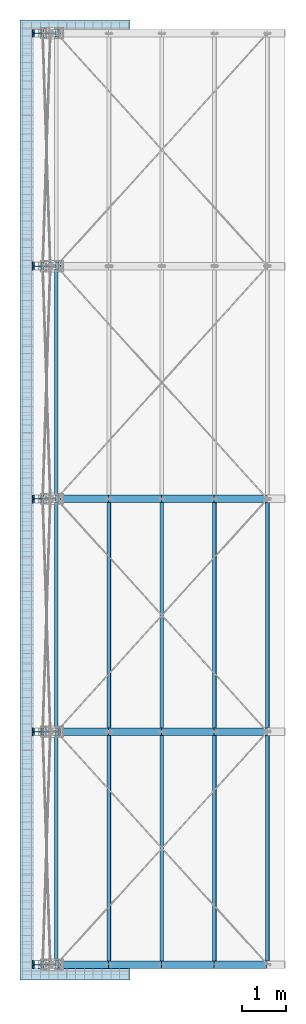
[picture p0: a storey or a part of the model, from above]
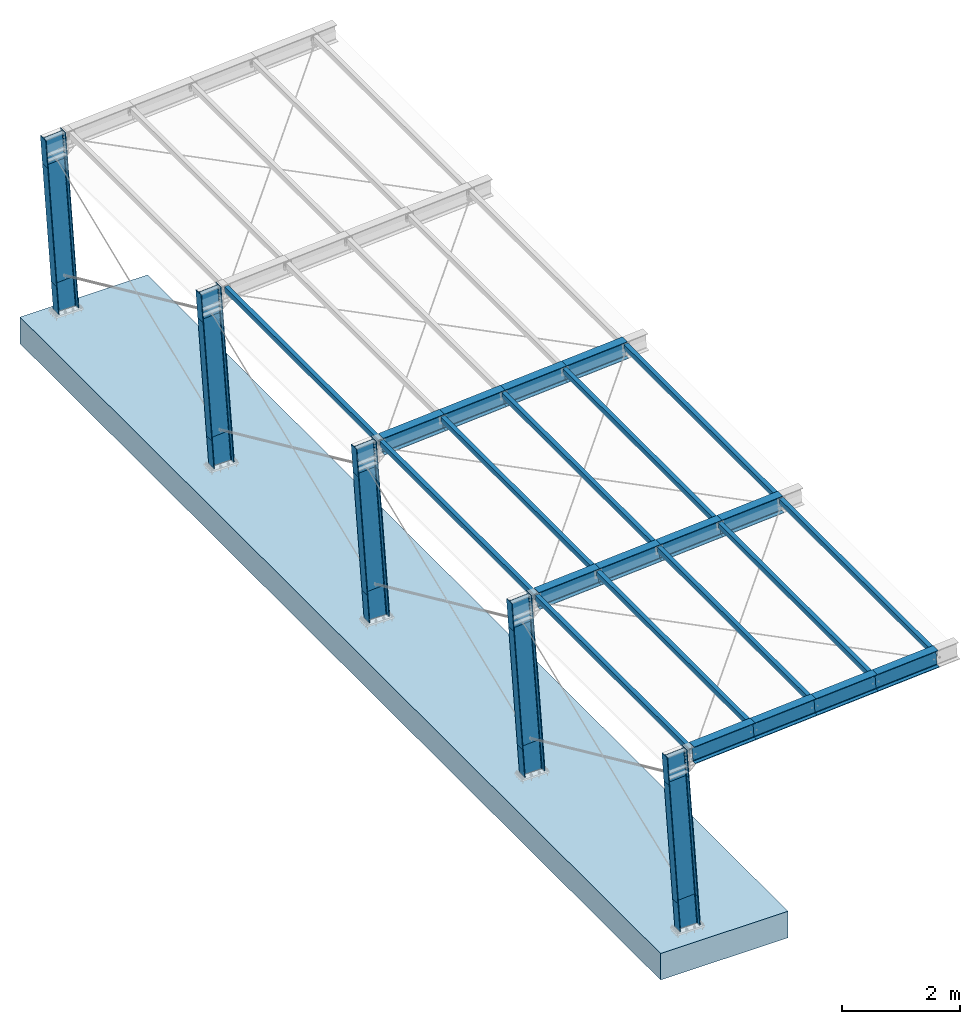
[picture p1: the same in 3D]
Properties of the parts of a building model (IFC4)

# File
Description: ViewDefinition [CoordinationView]
Made in: IFC file generated by ModeSt (Tecnisoft s.a.s.)

# IfcBuildingStorey, Storey 0
In: Pensilina
Elevation: 0 m

# IfcBeam: 3 IPE360 (30)
In: Storey 0
Type - PredefinedType: BEAM; Material: Acciaio
Description: 3 IPE360 - Acciaio
Pset_BeamCommon - LoadBearing: yes
BaseQuantities - ?: 0.0069948 m2
Name | BaseQuantities, ? (m3) | BaseQuantities, ? (m)
701 | 0.00374222 | 0.535
701 | 0.00839342 | 1.19995
2 x 701 | 0.00839397 | 1.20003
701 | 0.00279779 | 0.399981
702 | 0.00374222 | 0.535
702 | 0.00839342 | 1.19995
702 | 0.00839397 | 1.20003
702 | 0.00839396 | 1.20003
702 | 0.00279779 | 0.399981
703 | 0.00374222 | 0.535
703 | 0.00839342 | 1.19995
703 | 0.00839397 | 1.20003
703 | 0.00839396 | 1.20003
703 | 0.00279779 | 0.399981
704 | 0.00374222 | 0.535
704 | 0.00839342 | 1.19995
704 | 0.00839397 | 1.20003
704 | 0.00839396 | 1.20003
704 | 0.00279779 | 0.399981
705 | 0.00374222 | 0.535
705 | 0.00839342 | 1.19995
705 | 0.00839397 | 1.20003
705 | 0.00839396 | 1.20003
705 | 0.00279779 | 0.399981
701 | 0.00839406 | 1.20004
702 | 0.00839406 | 1.20004
703 | 0.00839406 | 1.20004
704 | 0.00839406 | 1.20004
705 | 0.00839406 | 1.20004

# IfcBeam: 9 RHS120x80x5 (20)
In: Storey 0
Type - PredefinedType: BEAM; Material: Acciaio
Description: 9 RHS120x80x5 - Acciaio
Pset_BeamCommon - LoadBearing: yes
BaseQuantities - ?: 0.0019 m2; ?: 0.010032 m3; ?: 5.28 m
Name
4 x 307
4 x 408
4 x 509
4 x 610
4 x 206

# IfcBuildingElementProxy: 11 C16 (8)
In: Storey 0
Type - PredefinedType: MEMBER; Material: Acciaio
Description: 11 C16 - Acciaio
Pset_MemberCommon - LoadBearing: yes
BaseQuantities - ?: 0.000197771 m2; ?: 0.00115711 m3; ?: 5.85075 m
Name
914
911
916
918
919
921
926
925

# IfcBuildingElementProxy: 12 C20 (8)
In: Storey 0
Type - PredefinedType: MEMBER; Material: Acciaio
Description: 12 C20 - Acciaio
Pset_MemberCommon - LoadBearing: yes
BaseQuantities - ?: 0.000309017 m2; ?: 0.00220507 m3; ?: 7.13575 m
Name
612
613
617
615
620
622
624
623

# IfcColumn: 1 IPE400 (15)
In: Storey 0
Type - PredefinedType: COLUMN; Material: Acciaio
Description: 1 IPE400 - Acciaio
Pset_ColumnCommon - LoadBearing: yes
BaseQuantities - ?: 0.0080678 m2
Name | BaseQuantities, ? (m3) | BaseQuantities, ? (m)
101 | 0.00564746 | 0.7
101 | 0.0203349 | 2.5205
102 | 0.00564746 | 0.7
102 | 0.0203349 | 2.5205
102 | 0.00329193 | 0.408033
103 | 0.00564746 | 0.7
103 | 0.0203349 | 2.5205
103 | 0.00329193 | 0.408033
104 | 0.00564746 | 0.7
104 | 0.0203349 | 2.5205
104 | 0.00329193 | 0.408033
105 | 0.00564746 | 0.7
105 | 0.0203349 | 2.5205
105 | 0.00329193 | 0.408033
101 | 0.00329193 | 0.408033

# IfcFastener: Collegamento -196_-202 (2)
In: Storey 0
Type - PredefinedType: WELD
Description: 11x11

# IfcFastener: Collegamento -197_-201 (2)
In: Storey 0
Type - PredefinedType: WELD
Description: 11x11

# IfcFastener: Collegamento -197_-203 (2)
In: Storey 0
Type - PredefinedType: WELD
Description: 11x11

# IfcFastener: Collegamento -198_-202 (2)
In: Storey 0
Type - PredefinedType: WELD
Description: 11x11

# IfcFastener: Collegamento -198_-204 (2)
In: Storey 0
Type - PredefinedType: WELD
Description: 11x11

# IfcFastener: Collegamento -199_-203 (2)
In: Storey 0
Type - PredefinedType: WELD
Description: 11x11

# IfcFastener: Collegamento -199_-205 (2)
In: Storey 0
Type - PredefinedType: WELD
Description: 11x11

# IfcFastener: Collegamento -200_-204 (2)
In: Storey 0
Type - PredefinedType: WELD
Description: 11x11

# IfcFastener: Collegamento -201_-197 (2)
In: Storey 0
Type - PredefinedType: WELD
Description: 11x11

# IfcFastener: Collegamento -202_-196 (2)
In: Storey 0
Type - PredefinedType: WELD
Description: 11x11

# IfcFastener: Collegamento -202_-198 (2)
In: Storey 0
Type - PredefinedType: WELD
Description: 11x11

# IfcFastener: Collegamento -203_-197 (2)
In: Storey 0
Type - PredefinedType: WELD
Description: 11x11

# IfcFastener: Collegamento -203_-199 (2)
In: Storey 0
Type - PredefinedType: WELD
Description: 11x11

# IfcFastener: Collegamento -204_-198 (2)
In: Storey 0
Type - PredefinedType: WELD
Description: 11x11

# IfcFastener: Collegamento -204_-200 (2)
In: Storey 0
Type - PredefinedType: WELD
Description: 11x11

# IfcFastener: Collegamento -205_-199 (2)
In: Storey 0
Type - PredefinedType: WELD
Description: 11x11

# IfcFastener: Collegamento 0001_-196 (16)
In: Storey 0
Type - PredefinedType: WELD
Description: 12x12

# IfcFastener: Collegamento 0002_-197 (16)
In: Storey 0
Type - PredefinedType: WELD
Description: 12x12

# IfcFastener: Collegamento 0003_-198 (16)
In: Storey 0
Type - PredefinedType: WELD
Description: 12x12

# IfcFastener: Collegamento 0004_-199 (16)
In: Storey 0
Type - PredefinedType: WELD
Description: 12x12

# IfcFastener: Collegamento 0005_-200 (16)
In: Storey 0
Type - PredefinedType: WELD
Description: 12x12

# IfcFastener: Collegamento 0101_0201 (20)
In: Storey 0
Type - PredefinedType: WELD
Name | Description
14 x Collegamento 0101_0201 | 10x10
6 x Collegamento 0101_0201 | 14x14

# IfcFastener: Collegamento 0102_0202 (20)
In: Storey 0
Type - PredefinedType: WELD
Name | Description
14 x Collegamento 0102_0202 | 10x10
6 x Collegamento 0102_0202 | 14x14

# IfcFastener: Collegamento 0103_0203 (20)
In: Storey 0
Type - PredefinedType: WELD
Name | Description
14 x Collegamento 0103_0203 | 10x10
6 x Collegamento 0103_0203 | 14x14

# IfcFastener: Collegamento 0104_0204 (20)
In: Storey 0
Type - PredefinedType: WELD
Name | Description
14 x Collegamento 0104_0204 | 10x10
6 x Collegamento 0104_0204 | 14x14

# IfcFastener: Collegamento 0105_0205 (20)
In: Storey 0
Type - PredefinedType: WELD
Name | Description
14 x Collegamento 0105_0205 | 10x10
6 x Collegamento 0105_0205 | 14x14

# IfcFastener: Collegamento 0201_0202 (8)
In: Storey 0
Type - PredefinedType: WELD
Description: 7x7

# IfcFastener: Collegamento 0201_0602 (2)
In: Storey 0
Type - PredefinedType: WELD
Description: 14x14

# IfcFastener: Collegamento 0202_0201 (8)
In: Storey 0
Type - PredefinedType: WELD
Description: 7x7

# IfcFastener: Collegamento 0202_0203 (8)
In: Storey 0
Type - PredefinedType: WELD
Description: 7x7

# IfcFastener: Collegamento 0202_0601 (2)
In: Storey 0
Type - PredefinedType: WELD
Description: 14x14

# IfcFastener: Collegamento 0202_0603 (2)
In: Storey 0
Type - PredefinedType: WELD
Description: 14x14

# IfcFastener: Collegamento 0203_0202 (8)
In: Storey 0
Type - PredefinedType: WELD
Description: 7x7

# IfcFastener: Collegamento 0203_0204 (8)
In: Storey 0
Type - PredefinedType: WELD
Description: 7x7

# IfcFastener: Collegamento 0203_0602 (2)
In: Storey 0
Type - PredefinedType: WELD
Description: 14x14

# IfcFastener: Collegamento 0203_0604 (2)
In: Storey 0
Type - PredefinedType: WELD
Description: 14x14

# IfcFastener: Collegamento 0204_0203 (8)
In: Storey 0
Type - PredefinedType: WELD
Description: 7x7

# IfcFastener: Collegamento 0204_0205 (8)
In: Storey 0
Type - PredefinedType: WELD
Description: 7x7

# IfcFastener: Collegamento 0204_0603 (2)
In: Storey 0
Type - PredefinedType: WELD
Description: 14x14

# IfcFastener: Collegamento 0204_0605 (2)
In: Storey 0
Type - PredefinedType: WELD
Description: 14x14

# IfcFastener: Collegamento 0205_0204 (8)
In: Storey 0
Type - PredefinedType: WELD
Description: 7x7

# IfcFastener: Collegamento 0205_0604 (2)
In: Storey 0
Type - PredefinedType: WELD
Description: 14x14

# IfcFastener: Collegamento 0301_0302 (8)
In: Storey 0
Type - PredefinedType: WELD
Description: 7x7

# IfcFastener: Collegamento 0302_0301 (8)
In: Storey 0
Type - PredefinedType: WELD
Description: 7x7

# IfcFastener: Collegamento 0302_0303 (8)
In: Storey 0
Type - PredefinedType: WELD
Description: 7x7

# IfcFastener: Collegamento 0303_0302 (8)
In: Storey 0
Type - PredefinedType: WELD
Description: 7x7

# IfcFastener: Collegamento 0303_0304 (8)
In: Storey 0
Type - PredefinedType: WELD
Description: 7x7

# IfcFastener: Collegamento 0304_0303 (8)
In: Storey 0
Type - PredefinedType: WELD
Description: 7x7

# IfcFastener: Collegamento 0304_0305 (8)
In: Storey 0
Type - PredefinedType: WELD
Description: 7x7

# IfcFastener: Collegamento 0305_0304 (8)
In: Storey 0
Type - PredefinedType: WELD
Description: 7x7

# IfcFastener: Collegamento 0401_0402 (8)
In: Storey 0
Type - PredefinedType: WELD
Description: 7x7

# IfcFastener: Collegamento 0402_0401 (8)
In: Storey 0
Type - PredefinedType: WELD
Description: 7x7

# IfcFastener: Collegamento 0402_0403 (8)
In: Storey 0
Type - PredefinedType: WELD
Description: 7x7

# IfcFastener: Collegamento 0403_0402 (8)
In: Storey 0
Type - PredefinedType: WELD
Description: 7x7

# IfcFastener: Collegamento 0403_0404 (8)
In: Storey 0
Type - PredefinedType: WELD
Description: 7x7

# IfcFastener: Collegamento 0404_0403 (8)
In: Storey 0
Type - PredefinedType: WELD
Description: 7x7

# IfcFastener: Collegamento 0404_0405 (8)
In: Storey 0
Type - PredefinedType: WELD
Description: 7x7

# IfcFastener: Collegamento 0405_0404 (8)
In: Storey 0
Type - PredefinedType: WELD
Description: 7x7

# IfcFastener: Collegamento 0501_0502 (8)
In: Storey 0
Type - PredefinedType: WELD
Description: 7x7

# IfcFastener: Collegamento 0502_0501 (8)
In: Storey 0
Type - PredefinedType: WELD
Description: 7x7

# IfcFastener: Collegamento 0502_0503 (8)
In: Storey 0
Type - PredefinedType: WELD
Description: 7x7

# IfcFastener: Collegamento 0503_0502 (8)
In: Storey 0
Type - PredefinedType: WELD
Description: 7x7

# IfcFastener: Collegamento 0503_0504 (8)
In: Storey 0
Type - PredefinedType: WELD
Description: 7x7

# IfcFastener: Collegamento 0504_0503 (8)
In: Storey 0
Type - PredefinedType: WELD
Description: 7x7

# IfcFastener: Collegamento 0504_0505 (8)
In: Storey 0
Type - PredefinedType: WELD
Description: 7x7

# IfcFastener: Collegamento 0505_0504 (8)
In: Storey 0
Type - PredefinedType: WELD
Description: 7x7

# IfcFastener: Collegamento 0601_0202 (2)
In: Storey 0
Type - PredefinedType: WELD
Description: 14x14

# IfcFastener: Collegamento 0601_0602 (8)
In: Storey 0
Type - PredefinedType: WELD
Description: 7x7

# IfcFastener: Collegamento 0602_0201 (2)
In: Storey 0
Type - PredefinedType: WELD
Description: 14x14

# IfcFastener: Collegamento 0602_0203 (2)
In: Storey 0
Type - PredefinedType: WELD
Description: 14x14

# IfcFastener: Collegamento 0602_0601 (8)
In: Storey 0
Type - PredefinedType: WELD
Description: 7x7

# IfcFastener: Collegamento 0602_0603 (8)
In: Storey 0
Type - PredefinedType: WELD
Description: 7x7

# IfcFastener: Collegamento 0603_0202 (2)
In: Storey 0
Type - PredefinedType: WELD
Description: 14x14

# IfcFastener: Collegamento 0603_0204 (2)
In: Storey 0
Type - PredefinedType: WELD
Description: 14x14

# IfcFastener: Collegamento 0603_0602 (8)
In: Storey 0
Type - PredefinedType: WELD
Description: 7x7

# IfcFastener: Collegamento 0603_0604 (8)
In: Storey 0
Type - PredefinedType: WELD
Description: 7x7

# IfcFastener: Collegamento 0604_0203 (2)
In: Storey 0
Type - PredefinedType: WELD
Description: 14x14

# IfcFastener: Collegamento 0604_0205 (2)
In: Storey 0
Type - PredefinedType: WELD
Description: 14x14

# IfcFastener: Collegamento 0604_0603 (8)
In: Storey 0
Type - PredefinedType: WELD
Description: 7x7

# IfcFastener: Collegamento 0604_0605 (8)
In: Storey 0
Type - PredefinedType: WELD
Description: 7x7

# IfcFastener: Collegamento 0605_0204 (2)
In: Storey 0
Type - PredefinedType: WELD
Description: 14x14

# IfcFastener: Collegamento 0605_0604 (8)
In: Storey 0
Type - PredefinedType: WELD
Description: 7x7

# IfcFooting: 1 fondazione
In: Storey 0
Type - PredefinedType: STRIP_FOOTING
Description: 1 fondazione; Material: Calcestruzzo classe C25/30 0.55 m
Pset_WallCommon - LoadBearing: yes
BaseQuantities - ?: 29.9337 m3

# IfcMechanicalFastener: Collegamento -196_-202 (4)
In: Storey 0
Type - PredefinedType: BOLT
Name | Description | NominalDiameter (m)
3 x Collegamento -196_-202 | M12 | 0.012
Collegamento -196_-202 | M24 | 0.024

# IfcMechanicalFastener: Collegamento -197_-201 (4)
In: Storey 0
Type - PredefinedType: BOLT
Name | Description | NominalDiameter (m)
2 x Collegamento -197_-201 | M12 | 0.0119999
Collegamento -197_-201 | M12 | 0.012
Collegamento -197_-201 | M24 | 0.024

# IfcMechanicalFastener: Collegamento -197_-203 (4)
In: Storey 0
Type - PredefinedType: BOLT
Name | Description | NominalDiameter (m)
2 x Collegamento -197_-203 | M12 | 0.0119999
Collegamento -197_-203 | M12 | 0.012
Collegamento -197_-203 | M24 | 0.024

# IfcMechanicalFastener: Collegamento -198_-202 (4)
In: Storey 0
Type - PredefinedType: BOLT
Name | Description | NominalDiameter (m)
Collegamento -198_-202 | M12 | 0.0119996
Collegamento -198_-202 | M12 | 0.012
Collegamento -198_-202 | M12 | 0.0119995
Collegamento -198_-202 | M24 | 0.024

# IfcMechanicalFastener: Collegamento -198_-204 (4)
In: Storey 0
Type - PredefinedType: BOLT
Name | Description | NominalDiameter (m)
Collegamento -198_-204 | M12 | 0.0119995
Collegamento -198_-204 | M12 | 0.012
Collegamento -198_-204 | M12 | 0.0119996
Collegamento -198_-204 | M24 | 0.024

# IfcMechanicalFastener: Collegamento -199_-203 (4)
In: Storey 0
Type - PredefinedType: BOLT
Name | Description | NominalDiameter (m)
2 x Collegamento -199_-203 | M12 | 0.0119995
Collegamento -199_-203 | M12 | 0.012
Collegamento -199_-203 | M24 | 0.024

# IfcMechanicalFastener: Collegamento -199_-205 (4)
In: Storey 0
Type - PredefinedType: BOLT
Name | Description | NominalDiameter (m)
Collegamento -199_-205 | M12 | 0.0119996
Collegamento -199_-205 | M12 | 0.012
Collegamento -199_-205 | M12 | 0.0119995
Collegamento -199_-205 | M24 | 0.024

# IfcMechanicalFastener: Collegamento -200_-204 (4)
In: Storey 0
Type - PredefinedType: BOLT
Name | Description | NominalDiameter (m)
2 x Collegamento -200_-204 | M12 | 0.0119995
Collegamento -200_-204 | M12 | 0.012
Collegamento -200_-204 | M24 | 0.024

# IfcMechanicalFastener: Collegamento -201_-197 (4)
In: Storey 0
Type - PredefinedType: BOLT
Name | Description | NominalDiameter (m)
2 x Collegamento -201_-197 | M12 | 0.0119999
Collegamento -201_-197 | M12 | 0.012
Collegamento -201_-197 | M24 | 0.024

# IfcMechanicalFastener: Collegamento -202_-196 (4)
In: Storey 0
Type - PredefinedType: BOLT
Name | Description | NominalDiameter (m)
Collegamento -202_-196 | M12 | 0.0119997
Collegamento -202_-196 | M12 | 0.012
Collegamento -202_-196 | M12 | 0.0119999
Collegamento -202_-196 | M24 | 0.024

# IfcMechanicalFastener: Collegamento -202_-198 (4)
In: Storey 0
Type - PredefinedType: BOLT
Name | Description | NominalDiameter (m)
Collegamento -202_-198 | M12 | 0.0119998
Collegamento -202_-198 | M12 | 0.012
Collegamento -202_-198 | M12 | 0.0119997
Collegamento -202_-198 | M24 | 0.024

# IfcMechanicalFastener: Collegamento -203_-197 (4)
In: Storey 0
Type - PredefinedType: BOLT
Name | Description | NominalDiameter (m)
Collegamento -203_-197 | M12 | 0.0119997
Collegamento -203_-197 | M12 | 0.012
Collegamento -203_-197 | M12 | 0.0119996
Collegamento -203_-197 | M24 | 0.024

# IfcMechanicalFastener: Collegamento -203_-199 (4)
In: Storey 0
Type - PredefinedType: BOLT
Name | Description | NominalDiameter (m)
Collegamento -203_-199 | M12 | 0.0119994
Collegamento -203_-199 | M12 | 0.012
Collegamento -203_-199 | M12 | 0.0119997
Collegamento -203_-199 | M24 | 0.024

# IfcMechanicalFastener: Collegamento -204_-198 (4)
In: Storey 0
Type - PredefinedType: BOLT
Name | Description | NominalDiameter (m)
Collegamento -204_-198 | M12 | 0.0119997
Collegamento -204_-198 | M12 | 0.012
Collegamento -204_-198 | M12 | 0.0119996
Collegamento -204_-198 | M24 | 0.024

# IfcMechanicalFastener: Collegamento -204_-200 (4)
In: Storey 0
Type - PredefinedType: BOLT
Name | Description | NominalDiameter (m)
Collegamento -204_-200 | M12 | 0.0119997
Collegamento -204_-200 | M12 | 0.012
Collegamento -204_-200 | M12 | 0.0119996
Collegamento -204_-200 | M24 | 0.024

# IfcMechanicalFastener: Collegamento -205_-199 (4)
In: Storey 0
Type - PredefinedType: BOLT
Name | Description | NominalDiameter (m)
2 x Collegamento -205_-199 | M12 | 0.0119994
Collegamento -205_-199 | M12 | 0.012
Collegamento -205_-199 | M24 | 0.024

# IfcMechanicalFastener: Collegamento 0001_-196 (60)
In: Storey 0
Type - PredefinedType: BOLT
Name | Description | NominalDiameter (m)
36 x Collegamento 0001_-196 | M16 | 0.016
24 x Collegamento 0001_-196 | M32 | 0.032

# IfcMechanicalFastener: Collegamento 0002_-197 (60)
In: Storey 0
Type - PredefinedType: BOLT
Name | Description | NominalDiameter (m)
24 x Collegamento 0002_-197 | M16 | 0.016
24 x Collegamento 0002_-197 | M32 | 0.032
12 x Collegamento 0002_-197 | M16 | 0.0159998

# IfcMechanicalFastener: Collegamento 0003_-198 (60)
In: Storey 0
Type - PredefinedType: BOLT
Name | Description | NominalDiameter (m)
36 x Collegamento 0003_-198 | M16 | 0.0159997
24 x Collegamento 0003_-198 | M32 | 0.032

# IfcMechanicalFastener: Collegamento 0004_-199 (60)
In: Storey 0
Type - PredefinedType: BOLT
Name | Description | NominalDiameter (m)
36 x Collegamento 0004_-199 | M16 | 0.0159997
24 x Collegamento 0004_-199 | M32 | 0.032

# IfcMechanicalFastener: Collegamento 0005_-200 (60)
In: Storey 0
Type - PredefinedType: BOLT
Name | Description | NominalDiameter (m)
24 x Collegamento 0005_-200 | M16 | 0.0159997
24 x Collegamento 0005_-200 | M32 | 0.032
12 x Collegamento 0005_-200 | M16 | 0.0159988

# IfcMechanicalFastener: Collegamento 0101_0201 (48)
In: Storey 0
Type - PredefinedType: BOLT
Name | Description | NominalDiameter (m)
16 x Collegamento 0101_0201 | M14 | 0.0139999
20 x Collegamento 0101_0201 | M14 | 0.014
12 x Collegamento 0101_0201 | M28 | 0.028

# IfcMechanicalFastener: Collegamento 0102_0202 (48)
In: Storey 0
Type - PredefinedType: BOLT
Name | Description | NominalDiameter (m)
24 x Collegamento 0102_0202 | M14 | 0.0139999
12 x Collegamento 0102_0202 | M14 | 0.014
12 x Collegamento 0102_0202 | M28 | 0.028

# IfcMechanicalFastener: Collegamento 0103_0203 (48)
In: Storey 0
Type - PredefinedType: BOLT
Name | Description | NominalDiameter (m)
24 x Collegamento 0103_0203 | M14 | 0.0139999
12 x Collegamento 0103_0203 | M14 | 0.014
12 x Collegamento 0103_0203 | M28 | 0.028

# IfcMechanicalFastener: Collegamento 0104_0204 (48)
In: Storey 0
Type - PredefinedType: BOLT
Name | Description | NominalDiameter (m)
24 x Collegamento 0104_0204 | M14 | 0.0139999
12 x Collegamento 0104_0204 | M14 | 0.014
12 x Collegamento 0104_0204 | M28 | 0.028

# IfcMechanicalFastener: Collegamento 0105_0205 (48)
In: Storey 0
Type - PredefinedType: BOLT
Name | Description | NominalDiameter (m)
24 x Collegamento 0105_0205 | M14 | 0.0139999
12 x Collegamento 0105_0205 | M14 | 0.014
12 x Collegamento 0105_0205 | M28 | 0.028

# IfcMechanicalFastener: Collegamento 0201_0202 (16)
In: Storey 0
Type - PredefinedType: BOLT
Name | Description | NominalDiameter (m)
8 x Collegamento 0201_0202 | M12 | 0.0119999
4 x Collegamento 0201_0202 | M12 | 0.012
4 x Collegamento 0201_0202 | M24 | 0.024

# IfcMechanicalFastener: Collegamento 0201_0602 (4)
In: Storey 0
Type - PredefinedType: BOLT
Name | Description | NominalDiameter (m)
3 x Collegamento 0201_0602 | M12 | 0.012
Collegamento 0201_0602 | M24 | 0.024

# IfcMechanicalFastener: Collegamento 0202_0201 (16)
In: Storey 0
Type - PredefinedType: BOLT
Name | Description | NominalDiameter (m)
8 x Collegamento 0202_0201 | M12 | 0.0119999
4 x Collegamento 0202_0201 | M12 | 0.012
4 x Collegamento 0202_0201 | M24 | 0.024

# IfcMechanicalFastener: Collegamento 0202_0203 (16)
In: Storey 0
Type - PredefinedType: BOLT
Name | Description | NominalDiameter (m)
8 x Collegamento 0202_0203 | M12 | 0.0119999
4 x Collegamento 0202_0203 | M12 | 0.012
4 x Collegamento 0202_0203 | M24 | 0.024

# IfcMechanicalFastener: Collegamento 0202_0601 (4)
In: Storey 0
Type - PredefinedType: BOLT
Name | Description | NominalDiameter (m)
Collegamento 0202_0601 | M12 | 0.0119999
2 x Collegamento 0202_0601 | M12 | 0.012
Collegamento 0202_0601 | M24 | 0.024

# IfcMechanicalFastener: Collegamento 0202_0603 (4)
In: Storey 0
Type - PredefinedType: BOLT
Name | Description | NominalDiameter (m)
2 x Collegamento 0202_0603 | M12 | 0.0119999
Collegamento 0202_0603 | M12 | 0.012
Collegamento 0202_0603 | M24 | 0.024

# IfcMechanicalFastener: Collegamento 0203_0202 (16)
In: Storey 0
Type - PredefinedType: BOLT
Name | Description | NominalDiameter (m)
8 x Collegamento 0203_0202 | M12 | 0.0119999
4 x Collegamento 0203_0202 | M12 | 0.012
4 x Collegamento 0203_0202 | M24 | 0.024

# IfcMechanicalFastener: Collegamento 0203_0204 (16)
In: Storey 0
Type - PredefinedType: BOLT
Name | Description | NominalDiameter (m)
8 x Collegamento 0203_0204 | M12 | 0.0119999
4 x Collegamento 0203_0204 | M12 | 0.012
4 x Collegamento 0203_0204 | M24 | 0.024

# IfcMechanicalFastener: Collegamento 0203_0602 (4)
In: Storey 0
Type - PredefinedType: BOLT
Name | Description | NominalDiameter (m)
2 x Collegamento 0203_0602 | M12 | 0.0119996
Collegamento 0203_0602 | M12 | 0.012
Collegamento 0203_0602 | M24 | 0.024

# IfcMechanicalFastener: Collegamento 0203_0604 (4)
In: Storey 0
Type - PredefinedType: BOLT
Name | Description | NominalDiameter (m)
2 x Collegamento 0203_0604 | M12 | 0.0119996
Collegamento 0203_0604 | M12 | 0.012
Collegamento 0203_0604 | M24 | 0.024

# IfcMechanicalFastener: Collegamento 0204_0203 (16)
In: Storey 0
Type - PredefinedType: BOLT
Name | Description | NominalDiameter (m)
8 x Collegamento 0204_0203 | M12 | 0.0119999
4 x Collegamento 0204_0203 | M12 | 0.012
4 x Collegamento 0204_0203 | M24 | 0.024

# IfcMechanicalFastener: Collegamento 0204_0205 (16)
In: Storey 0
Type - PredefinedType: BOLT
Name | Description | NominalDiameter (m)
8 x Collegamento 0204_0205 | M12 | 0.0119999
4 x Collegamento 0204_0205 | M12 | 0.012
4 x Collegamento 0204_0205 | M24 | 0.024

# IfcMechanicalFastener: Collegamento 0204_0603 (4)
In: Storey 0
Type - PredefinedType: BOLT
Name | Description | NominalDiameter (m)
2 x Collegamento 0204_0603 | M12 | 0.0119996
Collegamento 0204_0603 | M12 | 0.012
Collegamento 0204_0603 | M24 | 0.024

# IfcMechanicalFastener: Collegamento 0204_0605 (4)
In: Storey 0
Type - PredefinedType: BOLT
Name | Description | NominalDiameter (m)
2 x Collegamento 0204_0605 | M12 | 0.0119996
Collegamento 0204_0605 | M12 | 0.012
Collegamento 0204_0605 | M24 | 0.024

# IfcMechanicalFastener: Collegamento 0205_0204 (16)
In: Storey 0
Type - PredefinedType: BOLT
Name | Description | NominalDiameter (m)
8 x Collegamento 0205_0204 | M12 | 0.0119999
4 x Collegamento 0205_0204 | M12 | 0.012
4 x Collegamento 0205_0204 | M24 | 0.024

# IfcMechanicalFastener: Collegamento 0205_0604 (4)
In: Storey 0
Type - PredefinedType: BOLT
Name | Description | NominalDiameter (m)
2 x Collegamento 0205_0604 | M12 | 0.0119996
Collegamento 0205_0604 | M12 | 0.012
Collegamento 0205_0604 | M24 | 0.024

# IfcMechanicalFastener: Collegamento 0301_0302 (16)
In: Storey 0
Type - PredefinedType: BOLT
Name | Description | NominalDiameter (m)
8 x Collegamento 0301_0302 | M12 | 0.0119999
4 x Collegamento 0301_0302 | M12 | 0.012
4 x Collegamento 0301_0302 | M24 | 0.024

# IfcMechanicalFastener: Collegamento 0302_0301 (16)
In: Storey 0
Type - PredefinedType: BOLT
Name | Description | NominalDiameter (m)
8 x Collegamento 0302_0301 | M12 | 0.0119999
4 x Collegamento 0302_0301 | M12 | 0.012
4 x Collegamento 0302_0301 | M24 | 0.024

# IfcMechanicalFastener: Collegamento 0302_0303 (16)
In: Storey 0
Type - PredefinedType: BOLT
Name | Description | NominalDiameter (m)
8 x Collegamento 0302_0303 | M12 | 0.0119999
4 x Collegamento 0302_0303 | M12 | 0.012
4 x Collegamento 0302_0303 | M24 | 0.024

# IfcMechanicalFastener: Collegamento 0303_0302 (16)
In: Storey 0
Type - PredefinedType: BOLT
Name | Description | NominalDiameter (m)
8 x Collegamento 0303_0302 | M12 | 0.0119999
4 x Collegamento 0303_0302 | M12 | 0.012
4 x Collegamento 0303_0302 | M24 | 0.024

# IfcMechanicalFastener: Collegamento 0303_0304 (16)
In: Storey 0
Type - PredefinedType: BOLT
Name | Description | NominalDiameter (m)
8 x Collegamento 0303_0304 | M12 | 0.0119999
4 x Collegamento 0303_0304 | M12 | 0.012
4 x Collegamento 0303_0304 | M24 | 0.024

# IfcMechanicalFastener: Collegamento 0304_0303 (16)
In: Storey 0
Type - PredefinedType: BOLT
Name | Description | NominalDiameter (m)
8 x Collegamento 0304_0303 | M12 | 0.0119999
4 x Collegamento 0304_0303 | M12 | 0.012
4 x Collegamento 0304_0303 | M24 | 0.024

# IfcMechanicalFastener: Collegamento 0304_0305 (16)
In: Storey 0
Type - PredefinedType: BOLT
Name | Description | NominalDiameter (m)
8 x Collegamento 0304_0305 | M12 | 0.0119999
4 x Collegamento 0304_0305 | M12 | 0.012
4 x Collegamento 0304_0305 | M24 | 0.024

# IfcMechanicalFastener: Collegamento 0305_0304 (16)
In: Storey 0
Type - PredefinedType: BOLT
Name | Description | NominalDiameter (m)
8 x Collegamento 0305_0304 | M12 | 0.0119999
4 x Collegamento 0305_0304 | M12 | 0.012
4 x Collegamento 0305_0304 | M24 | 0.024

# IfcMechanicalFastener: Collegamento 0401_0402 (16)
In: Storey 0
Type - PredefinedType: BOLT
Name | Description | NominalDiameter (m)
8 x Collegamento 0401_0402 | M12 | 0.0119998
4 x Collegamento 0401_0402 | M12 | 0.012
4 x Collegamento 0401_0402 | M24 | 0.024

# IfcMechanicalFastener: Collegamento 0402_0401 (16)
In: Storey 0
Type - PredefinedType: BOLT
Name | Description | NominalDiameter (m)
8 x Collegamento 0402_0401 | M12 | 0.0119998
4 x Collegamento 0402_0401 | M12 | 0.012
4 x Collegamento 0402_0401 | M24 | 0.024

# IfcMechanicalFastener: Collegamento 0402_0403 (16)
In: Storey 0
Type - PredefinedType: BOLT
Name | Description | NominalDiameter (m)
8 x Collegamento 0402_0403 | M12 | 0.0119998
4 x Collegamento 0402_0403 | M12 | 0.012
4 x Collegamento 0402_0403 | M24 | 0.024

# IfcMechanicalFastener: Collegamento 0403_0402 (16)
In: Storey 0
Type - PredefinedType: BOLT
Name | Description | NominalDiameter (m)
8 x Collegamento 0403_0402 | M12 | 0.0119998
4 x Collegamento 0403_0402 | M12 | 0.012
4 x Collegamento 0403_0402 | M24 | 0.024

# IfcMechanicalFastener: Collegamento 0403_0404 (16)
In: Storey 0
Type - PredefinedType: BOLT
Name | Description | NominalDiameter (m)
8 x Collegamento 0403_0404 | M12 | 0.0119998
4 x Collegamento 0403_0404 | M12 | 0.012
4 x Collegamento 0403_0404 | M24 | 0.024

# IfcMechanicalFastener: Collegamento 0404_0403 (16)
In: Storey 0
Type - PredefinedType: BOLT
Name | Description | NominalDiameter (m)
8 x Collegamento 0404_0403 | M12 | 0.0119998
4 x Collegamento 0404_0403 | M12 | 0.012
4 x Collegamento 0404_0403 | M24 | 0.024

# IfcMechanicalFastener: Collegamento 0404_0405 (16)
In: Storey 0
Type - PredefinedType: BOLT
Name | Description | NominalDiameter (m)
8 x Collegamento 0404_0405 | M12 | 0.0119998
4 x Collegamento 0404_0405 | M12 | 0.012
4 x Collegamento 0404_0405 | M24 | 0.024

# IfcMechanicalFastener: Collegamento 0405_0404 (16)
In: Storey 0
Type - PredefinedType: BOLT
Name | Description | NominalDiameter (m)
8 x Collegamento 0405_0404 | M12 | 0.0119998
4 x Collegamento 0405_0404 | M12 | 0.012
4 x Collegamento 0405_0404 | M24 | 0.024

# IfcMechanicalFastener: Collegamento 0501_0502 (16)
In: Storey 0
Type - PredefinedType: BOLT
Name | Description | NominalDiameter (m)
4 x Collegamento 0501_0502 | M12 | 0.0119998
8 x Collegamento 0501_0502 | M12 | 0.012
4 x Collegamento 0501_0502 | M24 | 0.024

# IfcMechanicalFastener: Collegamento 0502_0501 (16)
In: Storey 0
Type - PredefinedType: BOLT
Name | Description | NominalDiameter (m)
4 x Collegamento 0502_0501 | M12 | 0.0119998
8 x Collegamento 0502_0501 | M12 | 0.012
4 x Collegamento 0502_0501 | M24 | 0.024

# IfcMechanicalFastener: Collegamento 0502_0503 (16)
In: Storey 0
Type - PredefinedType: BOLT
Name | Description | NominalDiameter (m)
4 x Collegamento 0502_0503 | M12 | 0.0119998
8 x Collegamento 0502_0503 | M12 | 0.012
4 x Collegamento 0502_0503 | M24 | 0.024

# IfcMechanicalFastener: Collegamento 0503_0502 (16)
In: Storey 0
Type - PredefinedType: BOLT
Name | Description | NominalDiameter (m)
4 x Collegamento 0503_0502 | M12 | 0.0119998
8 x Collegamento 0503_0502 | M12 | 0.012
4 x Collegamento 0503_0502 | M24 | 0.024

# IfcMechanicalFastener: Collegamento 0503_0504 (16)
In: Storey 0
Type - PredefinedType: BOLT
Name | Description | NominalDiameter (m)
4 x Collegamento 0503_0504 | M12 | 0.0119998
8 x Collegamento 0503_0504 | M12 | 0.012
4 x Collegamento 0503_0504 | M24 | 0.024

# IfcMechanicalFastener: Collegamento 0504_0503 (16)
In: Storey 0
Type - PredefinedType: BOLT
Name | Description | NominalDiameter (m)
4 x Collegamento 0504_0503 | M12 | 0.0119998
8 x Collegamento 0504_0503 | M12 | 0.012
4 x Collegamento 0504_0503 | M24 | 0.024

# IfcMechanicalFastener: Collegamento 0504_0505 (16)
In: Storey 0
Type - PredefinedType: BOLT
Name | Description | NominalDiameter (m)
4 x Collegamento 0504_0505 | M12 | 0.0119998
8 x Collegamento 0504_0505 | M12 | 0.012
4 x Collegamento 0504_0505 | M24 | 0.024

# IfcMechanicalFastener: Collegamento 0505_0504 (16)
In: Storey 0
Type - PredefinedType: BOLT
Name | Description | NominalDiameter (m)
4 x Collegamento 0505_0504 | M12 | 0.0119998
8 x Collegamento 0505_0504 | M12 | 0.012
4 x Collegamento 0505_0504 | M24 | 0.024

# IfcMechanicalFastener: Collegamento 0601_0202 (4)
In: Storey 0
Type - PredefinedType: BOLT
Name | Description | NominalDiameter (m)
Collegamento 0601_0202 | M12 | 0.0119996
2 x Collegamento 0601_0202 | M12 | 0.012
Collegamento 0601_0202 | M24 | 0.024

# IfcMechanicalFastener: Collegamento 0601_0602 (16)
In: Storey 0
Type - PredefinedType: BOLT
Name | Description | NominalDiameter (m)
4 x Collegamento 0601_0602 | M12 | 0.0119998
4 x Collegamento 0601_0602 | M12 | 0.012
4 x Collegamento 0601_0602 | M24 | 0.024
4 x Collegamento 0601_0602 | M12 | 0.0119996

# IfcMechanicalFastener: Collegamento 0602_0201 (4)
In: Storey 0
Type - PredefinedType: BOLT
Name | Description | NominalDiameter (m)
Collegamento 0602_0201 | M12 | 0.0119996
Collegamento 0602_0201 | M12 | 0.012
Collegamento 0602_0201 | M12 | 0.0119998
Collegamento 0602_0201 | M24 | 0.024

# IfcMechanicalFastener: Collegamento 0602_0203 (4)
In: Storey 0
Type - PredefinedType: BOLT
Name | Description | NominalDiameter (m)
2 x Collegamento 0602_0203 | M12 | 0.0119998
Collegamento 0602_0203 | M12 | 0.012
Collegamento 0602_0203 | M24 | 0.024

# IfcMechanicalFastener: Collegamento 0602_0601 (16)
In: Storey 0
Type - PredefinedType: BOLT
Name | Description | NominalDiameter (m)
4 x Collegamento 0602_0601 | M12 | 0.0119998
4 x Collegamento 0602_0601 | M12 | 0.012
4 x Collegamento 0602_0601 | M24 | 0.024
4 x Collegamento 0602_0601 | M12 | 0.0119996

# IfcMechanicalFastener: Collegamento 0602_0603 (16)
In: Storey 0
Type - PredefinedType: BOLT
Name | Description | NominalDiameter (m)
4 x Collegamento 0602_0603 | M12 | 0.0119998
8 x Collegamento 0602_0603 | M12 | 0.012
4 x Collegamento 0602_0603 | M24 | 0.024

# IfcMechanicalFastener: Collegamento 0603_0202 (4)
In: Storey 0
Type - PredefinedType: BOLT
Name | Description | NominalDiameter (m)
Collegamento 0603_0202 | M12 | 0.0119997
Collegamento 0603_0202 | M12 | 0.012
Collegamento 0603_0202 | M12 | 0.0119999
Collegamento 0603_0202 | M24 | 0.024

# IfcMechanicalFastener: Collegamento 0603_0204 (4)
In: Storey 0
Type - PredefinedType: BOLT
Name | Description | NominalDiameter (m)
Collegamento 0603_0204 | M12 | 0.0119994
Collegamento 0603_0204 | M12 | 0.012
Collegamento 0603_0204 | M12 | 0.0119997
Collegamento 0603_0204 | M24 | 0.024

# IfcMechanicalFastener: Collegamento 0603_0602 (16)
In: Storey 0
Type - PredefinedType: BOLT
Name | Description | NominalDiameter (m)
4 x Collegamento 0603_0602 | M12 | 0.0119998
8 x Collegamento 0603_0602 | M12 | 0.012
4 x Collegamento 0603_0602 | M24 | 0.024

# IfcMechanicalFastener: Collegamento 0603_0604 (16)
In: Storey 0
Type - PredefinedType: BOLT
Name | Description | NominalDiameter (m)
4 x Collegamento 0603_0604 | M12 | 0.0119998
8 x Collegamento 0603_0604 | M12 | 0.012
4 x Collegamento 0603_0604 | M24 | 0.024

# IfcMechanicalFastener: Collegamento 0604_0203 (4)
In: Storey 0
Type - PredefinedType: BOLT
Name | Description | NominalDiameter (m)
Collegamento 0604_0203 | M12 | 0.0119997
Collegamento 0604_0203 | M12 | 0.012
Collegamento 0604_0203 | M12 | 0.0119995
Collegamento 0604_0203 | M24 | 0.024

# IfcMechanicalFastener: Collegamento 0604_0205 (4)
In: Storey 0
Type - PredefinedType: BOLT
Name | Description | NominalDiameter (m)
Collegamento 0604_0205 | M12 | 0.0119994
Collegamento 0604_0205 | M12 | 0.012
Collegamento 0604_0205 | M12 | 0.0119997
Collegamento 0604_0205 | M24 | 0.024

# IfcMechanicalFastener: Collegamento 0604_0603 (16)
In: Storey 0
Type - PredefinedType: BOLT
Name | Description | NominalDiameter (m)
4 x Collegamento 0604_0603 | M12 | 0.0119998
8 x Collegamento 0604_0603 | M12 | 0.012
4 x Collegamento 0604_0603 | M24 | 0.024

# IfcMechanicalFastener: Collegamento 0604_0605 (16)
In: Storey 0
Type - PredefinedType: BOLT
Name | Description | NominalDiameter (m)
4 x Collegamento 0604_0605 | M12 | 0.0119998
8 x Collegamento 0604_0605 | M12 | 0.012
4 x Collegamento 0604_0605 | M24 | 0.024

# IfcMechanicalFastener: Collegamento 0605_0204 (4)
In: Storey 0
Type - PredefinedType: BOLT
Name | Description | NominalDiameter (m)
Collegamento 0605_0204 | M12 | 0.0119994
Collegamento 0605_0204 | M12 | 0.012
Collegamento 0605_0204 | M12 | 0.0119997
Collegamento 0605_0204 | M24 | 0.024

# IfcMechanicalFastener: Collegamento 0605_0604 (16)
In: Storey 0
Type - PredefinedType: BOLT
Name | Description | NominalDiameter (m)
4 x Collegamento 0605_0604 | M12 | 0.0119998
8 x Collegamento 0605_0604 | M12 | 0.012
4 x Collegamento 0605_0604 | M24 | 0.024

# IfcPlate: Collegamento -196_-202 (2)
In: Storey 0
Type - PredefinedType: SHEET

# IfcPlate: Collegamento -197_-201 (2)
In: Storey 0
Type - PredefinedType: SHEET

# IfcPlate: Collegamento -197_-203 (2)
In: Storey 0
Type - PredefinedType: SHEET

# IfcPlate: Collegamento -198_-202 (2)
In: Storey 0
Type - PredefinedType: SHEET

# IfcPlate: Collegamento -198_-204 (2)
In: Storey 0
Type - PredefinedType: SHEET

# IfcPlate: Collegamento -199_-203 (2)
In: Storey 0
Type - PredefinedType: SHEET

# IfcPlate: Collegamento -199_-205 (2)
In: Storey 0
Type - PredefinedType: SHEET

# IfcPlate: Collegamento -200_-204 (2)
In: Storey 0
Type - PredefinedType: SHEET

# IfcPlate: Collegamento -201_-197 (2)
In: Storey 0
Type - PredefinedType: SHEET

# IfcPlate: Collegamento -202_-196 (2)
In: Storey 0
Type - PredefinedType: SHEET

# IfcPlate: Collegamento -202_-198 (2)
In: Storey 0
Type - PredefinedType: SHEET

# IfcPlate: Collegamento -203_-197 (2)
In: Storey 0
Type - PredefinedType: SHEET

# IfcPlate: Collegamento -203_-199 (2)
In: Storey 0
Type - PredefinedType: SHEET

# IfcPlate: Collegamento -204_-198 (2)
In: Storey 0
Type - PredefinedType: SHEET

# IfcPlate: Collegamento -204_-200 (2)
In: Storey 0
Type - PredefinedType: SHEET

# IfcPlate: Collegamento -205_-199 (2)
In: Storey 0
Type - PredefinedType: SHEET

# IfcPlate: Collegamento 0001_-196
In: Storey 0
Type - PredefinedType: SHEET

# IfcPlate: Collegamento 0002_-197
In: Storey 0
Type - PredefinedType: SHEET

# IfcPlate: Collegamento 0003_-198
In: Storey 0
Type - PredefinedType: SHEET

# IfcPlate: Collegamento 0004_-199
In: Storey 0
Type - PredefinedType: SHEET

# IfcPlate: Collegamento 0005_-200
In: Storey 0
Type - PredefinedType: SHEET

# IfcPlate: Collegamento 0101_0201 (9)
In: Storey 0
Type - PredefinedType: SHEET

# IfcPlate: Collegamento 0102_0202 (9)
In: Storey 0
Type - PredefinedType: SHEET

# IfcPlate: Collegamento 0103_0203 (9)
In: Storey 0
Type - PredefinedType: SHEET

# IfcPlate: Collegamento 0104_0204 (9)
In: Storey 0
Type - PredefinedType: SHEET

# IfcPlate: Collegamento 0105_0205 (9)
In: Storey 0
Type - PredefinedType: SHEET

# IfcPlate: Collegamento 0201_0202
In: Storey 0
Type - PredefinedType: SHEET

# IfcPlate: Collegamento 0201_0602 (2)
In: Storey 0
Type - PredefinedType: SHEET

# IfcPlate: Collegamento 0202_0201
In: Storey 0
Type - PredefinedType: SHEET

# IfcPlate: Collegamento 0202_0203
In: Storey 0
Type - PredefinedType: SHEET

# IfcPlate: Collegamento 0202_0601 (2)
In: Storey 0
Type - PredefinedType: SHEET

# IfcPlate: Collegamento 0202_0603 (2)
In: Storey 0
Type - PredefinedType: SHEET

# IfcPlate: Collegamento 0203_0202
In: Storey 0
Type - PredefinedType: SHEET

# IfcPlate: Collegamento 0203_0204
In: Storey 0
Type - PredefinedType: SHEET

# IfcPlate: Collegamento 0203_0602 (2)
In: Storey 0
Type - PredefinedType: SHEET

# IfcPlate: Collegamento 0203_0604 (2)
In: Storey 0
Type - PredefinedType: SHEET

# IfcPlate: Collegamento 0204_0203
In: Storey 0
Type - PredefinedType: SHEET

# IfcPlate: Collegamento 0204_0205
In: Storey 0
Type - PredefinedType: SHEET

# IfcPlate: Collegamento 0204_0603 (2)
In: Storey 0
Type - PredefinedType: SHEET

# IfcPlate: Collegamento 0204_0605 (2)
In: Storey 0
Type - PredefinedType: SHEET

# IfcPlate: Collegamento 0205_0204
In: Storey 0
Type - PredefinedType: SHEET

# IfcPlate: Collegamento 0205_0604 (2)
In: Storey 0
Type - PredefinedType: SHEET

# IfcPlate: Collegamento 0301_0302
In: Storey 0
Type - PredefinedType: SHEET

# IfcPlate: Collegamento 0302_0301
In: Storey 0
Type - PredefinedType: SHEET

# IfcPlate: Collegamento 0302_0303
In: Storey 0
Type - PredefinedType: SHEET

# IfcPlate: Collegamento 0303_0302
In: Storey 0
Type - PredefinedType: SHEET

# IfcPlate: Collegamento 0303_0304
In: Storey 0
Type - PredefinedType: SHEET

# IfcPlate: Collegamento 0304_0303
In: Storey 0
Type - PredefinedType: SHEET

# IfcPlate: Collegamento 0304_0305
In: Storey 0
Type - PredefinedType: SHEET

# IfcPlate: Collegamento 0305_0304
In: Storey 0
Type - PredefinedType: SHEET

# IfcPlate: Collegamento 0401_0402
In: Storey 0
Type - PredefinedType: SHEET

# IfcPlate: Collegamento 0402_0401
In: Storey 0
Type - PredefinedType: SHEET

# IfcPlate: Collegamento 0402_0403
In: Storey 0
Type - PredefinedType: SHEET

# IfcPlate: Collegamento 0403_0402
In: Storey 0
Type - PredefinedType: SHEET

# IfcPlate: Collegamento 0403_0404
In: Storey 0
Type - PredefinedType: SHEET

# IfcPlate: Collegamento 0404_0403
In: Storey 0
Type - PredefinedType: SHEET

# IfcPlate: Collegamento 0404_0405
In: Storey 0
Type - PredefinedType: SHEET

# IfcPlate: Collegamento 0405_0404
In: Storey 0
Type - PredefinedType: SHEET

# IfcPlate: Collegamento 0501_0502
In: Storey 0
Type - PredefinedType: SHEET

# IfcPlate: Collegamento 0502_0501
In: Storey 0
Type - PredefinedType: SHEET

# IfcPlate: Collegamento 0502_0503
In: Storey 0
Type - PredefinedType: SHEET

# IfcPlate: Collegamento 0503_0502
In: Storey 0
Type - PredefinedType: SHEET

# IfcPlate: Collegamento 0503_0504
In: Storey 0
Type - PredefinedType: SHEET

# IfcPlate: Collegamento 0504_0503
In: Storey 0
Type - PredefinedType: SHEET

# IfcPlate: Collegamento 0504_0505
In: Storey 0
Type - PredefinedType: SHEET

# IfcPlate: Collegamento 0505_0504
In: Storey 0
Type - PredefinedType: SHEET

# IfcPlate: Collegamento 0601_0202 (2)
In: Storey 0
Type - PredefinedType: SHEET

# IfcPlate: Collegamento 0601_0602
In: Storey 0
Type - PredefinedType: SHEET

# IfcPlate: Collegamento 0602_0201 (2)
In: Storey 0
Type - PredefinedType: SHEET

# IfcPlate: Collegamento 0602_0203 (2)
In: Storey 0
Type - PredefinedType: SHEET

# IfcPlate: Collegamento 0602_0601
In: Storey 0
Type - PredefinedType: SHEET

# IfcPlate: Collegamento 0602_0603
In: Storey 0
Type - PredefinedType: SHEET

# IfcPlate: Collegamento 0603_0202 (2)
In: Storey 0
Type - PredefinedType: SHEET

# IfcPlate: Collegamento 0603_0204 (2)
In: Storey 0
Type - PredefinedType: SHEET

# IfcPlate: Collegamento 0603_0602
In: Storey 0
Type - PredefinedType: SHEET

# IfcPlate: Collegamento 0603_0604
In: Storey 0
Type - PredefinedType: SHEET

# IfcPlate: Collegamento 0604_0203 (2)
In: Storey 0
Type - PredefinedType: SHEET

# IfcPlate: Collegamento 0604_0205 (2)
In: Storey 0
Type - PredefinedType: SHEET

# IfcPlate: Collegamento 0604_0603
In: Storey 0
Type - PredefinedType: SHEET

# IfcPlate: Collegamento 0604_0605
In: Storey 0
Type - PredefinedType: SHEET

# IfcPlate: Collegamento 0605_0204 (2)
In: Storey 0
Type - PredefinedType: SHEET

# IfcPlate: Collegamento 0605_0604
In: Storey 0
Type - PredefinedType: SHEET

# IfcReinforcingBar (17)
In: Storey 0
Name | NominalDiameter (m) | CrossSectionArea (m2) | BarLength (m)
5 x  | 0.016 | 0.00020106 | 0.484
5 x  | 0.016 | 0.00020106 | 0.0187287
5 x  | 0.016 | 0.00020106 | 0.0479995
 | 0.012 | 0.0001131 | 3.32721 | SteelGrade: B450C
 | 0.012 | 0.0001131 | 22.5972 | SteelGrade: B450C

# IfcSlab: 1 Tettoia (24)
In: Storey 0
Type - PredefinedType: FLOOR; Material: CEMENTO ARMATO
Description: 1 Tettoia - Altezza solaio 0.050000 - Spessore cappa 0.000000 -
Pset_SlabCommon - LoadBearing: yes
BaseQuantities - ?: 0.05 m
Name | BaseQuantities, ? (m2) | BaseQuantities, ? (m3)
400 | -6.32084 | -0.316042
500 | -6.32126 | -0.316063
600 | -6.32125 | -0.316063
200 | -2.81816 | -0.140908
300 | -6.32132 | -0.316066
401 | -6.32084 | -0.316042
501 | -6.32126 | -0.316063
601 | -6.32125 | -0.316063
301 | -6.32132 | -0.316066
402 | -6.32084 | -0.316042
502 | -6.32126 | -0.316063
602 | -6.32125 | -0.316063
403 | -6.32084 | -0.316042
503 | -6.32125 | -0.316063
603 | -6.32125 | -0.316062
302 | -6.32132 | -0.316066
201 | -2.81816 | -0.140908
202 | -2.81816 | -0.140908
700 | -2.10693 | -0.105347
701 | -2.10693 | -0.105347
702 | -2.10693 | -0.105347
203 | -2.81816 | -0.140908
303 | -6.32132 | -0.316066
703 | -2.10693 | -0.105347

# IfcReinforcingBarType, no part of this type: type
PredefinedType: MAIN; NominalDiameter: 0.016 m; CrossSectionArea: 0.00020106 m2; BarLength: 0.484 m; Material: ACCIAIO

# IfcReinforcingBarType, no part of this type: type
PredefinedType: MAIN; NominalDiameter: 0.016 m; CrossSectionArea: 0.00020106 m2; BarLength: 0.0187287 m; Material: ACCIAIO

# IfcReinforcingBarType, no part of this type: type
PredefinedType: MAIN; NominalDiameter: 0.016 m; CrossSectionArea: 0.00020106 m2; BarLength: 0.0479995 m; Material: ACCIAIO

# IfcReinforcingBarType, no part of this type: type
PredefinedType: MAIN; NominalDiameter: 0.016 m; CrossSectionArea: 0.00020106 m2; BarLength: 0.484 m; Material: ACCIAIO

# IfcReinforcingBarType, no part of this type: type
PredefinedType: MAIN; NominalDiameter: 0.016 m; CrossSectionArea: 0.00020106 m2; BarLength: 0.0187287 m; Material: ACCIAIO

# IfcReinforcingBarType, no part of this type: type
PredefinedType: MAIN; NominalDiameter: 0.016 m; CrossSectionArea: 0.00020106 m2; BarLength: 0.0479995 m; Material: ACCIAIO

# IfcReinforcingBarType, no part of this type: type
PredefinedType: MAIN; NominalDiameter: 0.016 m; CrossSectionArea: 0.00020106 m2; BarLength: 0.484 m; Material: ACCIAIO

# IfcReinforcingBarType, no part of this type: type
PredefinedType: MAIN; NominalDiameter: 0.016 m; CrossSectionArea: 0.00020106 m2; BarLength: 0.0187287 m; Material: ACCIAIO

# IfcReinforcingBarType, no part of this type: type
PredefinedType: MAIN; NominalDiameter: 0.016 m; CrossSectionArea: 0.00020106 m2; BarLength: 0.0479995 m; Material: ACCIAIO

# IfcReinforcingBarType, no part of this type: type
PredefinedType: MAIN; NominalDiameter: 0.016 m; CrossSectionArea: 0.00020106 m2; BarLength: 0.484 m; Material: ACCIAIO

# IfcReinforcingBarType, no part of this type: type
PredefinedType: MAIN; NominalDiameter: 0.016 m; CrossSectionArea: 0.00020106 m2; BarLength: 0.0187287 m; Material: ACCIAIO

# IfcReinforcingBarType, no part of this type: type
PredefinedType: MAIN; NominalDiameter: 0.016 m; CrossSectionArea: 0.00020106 m2; BarLength: 0.0479995 m; Material: ACCIAIO

# IfcReinforcingBarType, no part of this type: type
PredefinedType: MAIN; NominalDiameter: 0.016 m; CrossSectionArea: 0.00020106 m2; BarLength: 0.484 m; Material: ACCIAIO

# IfcReinforcingBarType, no part of this type: type
PredefinedType: MAIN; NominalDiameter: 0.016 m; CrossSectionArea: 0.00020106 m2; BarLength: 0.0187287 m; Material: ACCIAIO

# IfcReinforcingBarType, no part of this type: type
PredefinedType: MAIN; NominalDiameter: 0.016 m; CrossSectionArea: 0.00020106 m2; BarLength: 0.0479995 m; Material: ACCIAIO

# IfcReinforcingBarType, no part of this type: type
PredefinedType: MAIN; NominalDiameter: 0.012 m; CrossSectionArea: 0.0001131 m2; BarLength: 3.32721 m; Material: ACCIAIO

# IfcReinforcingBarType, no part of this type: type
PredefinedType: MAIN; NominalDiameter: 0.012 m; CrossSectionArea: 0.0001131 m2; BarLength: 22.5972 m; Material: ACCIAIO

# Material: Acciaio
ACCIAIO - Mass Density: 7850; Poisson Ratio: 0.3; Shear Modulus: 8000000000; Thermal Expansion Coefficient: 0.00001; Young Modulus: 20999999488

# Material: Acciaio
ACCIAIO - Mass Density: 7850; Poisson Ratio: 0.3; Shear Modulus: 8000000000; Thermal Expansion Coefficient: 0.00001; Young Modulus: 20999999488

# Material: Acciaio
ACCIAIO - Mass Density: 7850; Poisson Ratio: 0.3; Shear Modulus: 8000000000; Thermal Expansion Coefficient: 0.00001; Young Modulus: 20999999488

# Material: Acciaio
ACCIAIO - Mass Density: 7850; Poisson Ratio: 0.3; Shear Modulus: 8000000000; Thermal Expansion Coefficient: 0.00001; Young Modulus: 20999999488

# Material: Acciaio
ACCIAIO - Mass Density: 7850; Poisson Ratio: 0.3; Shear Modulus: 8000000000; Thermal Expansion Coefficient: 0.00001; Young Modulus: 20999999488

# Material: Acciaio
ACCIAIO - Mass Density: 7850; Poisson Ratio: 0.3; Shear Modulus: 8000000000; Thermal Expansion Coefficient: 0.00001; Young Modulus: 20999999488

# Material: Acciaio
ACCIAIO - Mass Density: 7850; Poisson Ratio: 0.3; Shear Modulus: 8000000000; Thermal Expansion Coefficient: 0.00001; Young Modulus: 20999999488

# Material: Acciaio
ACCIAIO - Mass Density: 7850; Poisson Ratio: 0.3; Shear Modulus: 8000000000; Thermal Expansion Coefficient: 0.00001; Young Modulus: 20999999488

# Material: Acciaio
ACCIAIO - Mass Density: 7850; Poisson Ratio: 0.3; Shear Modulus: 8000000000; Thermal Expansion Coefficient: 0.00001; Young Modulus: 20999999488

# Material: Acciaio
ACCIAIO - Mass Density: 7850; Poisson Ratio: 0.3; Shear Modulus: 8000000000; Thermal Expansion Coefficient: 0.00001; Young Modulus: 20999999488

# Material: Acciaio
ACCIAIO - Mass Density: 7850; Poisson Ratio: 0.3; Shear Modulus: 8000000000; Thermal Expansion Coefficient: 0.00001; Young Modulus: 20999999488

# Material: Acciaio
ACCIAIO - Mass Density: 7850; Poisson Ratio: 0.3; Shear Modulus: 8000000000; Thermal Expansion Coefficient: 0.00001; Young Modulus: 20999999488

# Material: Acciaio
ACCIAIO - Mass Density: 7850; Poisson Ratio: 0.3; Shear Modulus: 8000000000; Thermal Expansion Coefficient: 0.00001; Young Modulus: 20999999488

# Material: Acciaio
ACCIAIO - Mass Density: 7850; Poisson Ratio: 0.3; Shear Modulus: 8000000000; Thermal Expansion Coefficient: 0.00001; Young Modulus: 20999999488

# Material: Acciaio
ACCIAIO - Mass Density: 7850; Poisson Ratio: 0.3; Shear Modulus: 8000000000; Thermal Expansion Coefficient: 0.00001; Young Modulus: 20999999488

# Material: Acciaio
ACCIAIO - Mass Density: 7850; Poisson Ratio: 0.3; Shear Modulus: 8000000000; Thermal Expansion Coefficient: 0.00001; Young Modulus: 20999999488

# Material: Acciaio
ACCIAIO - Mass Density: 7850; Poisson Ratio: 0.3; Shear Modulus: 8000000000; Thermal Expansion Coefficient: 0.00001; Young Modulus: 20999999488

# Material: Acciaio
ACCIAIO - Mass Density: 7850; Poisson Ratio: 0.3; Shear Modulus: 8000000000; Thermal Expansion Coefficient: 0.00001; Young Modulus: 20999999488

# Material: Acciaio
ACCIAIO - Mass Density: 7850; Poisson Ratio: 0.3; Shear Modulus: 8000000000; Thermal Expansion Coefficient: 0.00001; Young Modulus: 20999999488

# Material: Acciaio
ACCIAIO - Mass Density: 7850; Poisson Ratio: 0.3; Shear Modulus: 8000000000; Thermal Expansion Coefficient: 0.00001; Young Modulus: 20999999488

# Material: Acciaio
ACCIAIO - Mass Density: 7850; Poisson Ratio: 0.3; Shear Modulus: 8000000000; Thermal Expansion Coefficient: 0.00001; Young Modulus: 20999999488

# Material: Acciaio
ACCIAIO - Mass Density: 7850; Poisson Ratio: 0.3; Shear Modulus: 8000000000; Thermal Expansion Coefficient: 0.00001; Young Modulus: 20999999488

# Material: Acciaio
ACCIAIO - Mass Density: 7850; Poisson Ratio: 0.3; Shear Modulus: 8000000000; Thermal Expansion Coefficient: 0.00001; Young Modulus: 20999999488

# Material: Acciaio
ACCIAIO - Mass Density: 7850; Poisson Ratio: 0.3; Shear Modulus: 8000000000; Thermal Expansion Coefficient: 0.00001; Young Modulus: 20999999488

# Material: Acciaio
ACCIAIO - Mass Density: 7850; Poisson Ratio: 0.3; Shear Modulus: 8000000000; Thermal Expansion Coefficient: 0.00001; Young Modulus: 20999999488

# Material: Acciaio
ACCIAIO - Mass Density: 7850; Poisson Ratio: 0.3; Shear Modulus: 8000000000; Thermal Expansion Coefficient: 0.00001; Young Modulus: 20999999488

# Material: Acciaio
ACCIAIO - Mass Density: 7850; Poisson Ratio: 0.3; Shear Modulus: 8000000000; Thermal Expansion Coefficient: 0.00001; Young Modulus: 20999999488

# Material: Acciaio
ACCIAIO - Mass Density: 7850; Poisson Ratio: 0.3; Shear Modulus: 8000000000; Thermal Expansion Coefficient: 0.00001; Young Modulus: 20999999488

# Material: Acciaio
ACCIAIO - Mass Density: 7850; Poisson Ratio: 0.3; Shear Modulus: 8000000000; Thermal Expansion Coefficient: 0.00001; Young Modulus: 20999999488

# Material: Acciaio
ACCIAIO - Mass Density: 7850; Poisson Ratio: 0.3; Shear Modulus: 8000000000; Thermal Expansion Coefficient: 0.00001; Young Modulus: 20999999488

# Material: Acciaio
ACCIAIO - Mass Density: 7850; Poisson Ratio: 0.3; Shear Modulus: 8000000000; Thermal Expansion Coefficient: 0.00001; Young Modulus: 20999999488

# Material: Acciaio
ACCIAIO - Mass Density: 7850; Poisson Ratio: 0.3; Shear Modulus: 8000000000; Thermal Expansion Coefficient: 0.00001; Young Modulus: 20999999488

# Material: Acciaio
ACCIAIO - Mass Density: 7850; Poisson Ratio: 0.3; Shear Modulus: 8000000000; Thermal Expansion Coefficient: 0.00001; Young Modulus: 20999999488

# Material: Acciaio
ACCIAIO - Mass Density: 7850; Poisson Ratio: 0.3; Shear Modulus: 8000000000; Thermal Expansion Coefficient: 0.00001; Young Modulus: 20999999488

# Material: Acciaio
ACCIAIO - Mass Density: 7850; Poisson Ratio: 0.3; Shear Modulus: 8000000000; Thermal Expansion Coefficient: 0.00001; Young Modulus: 20999999488

# Material: Acciaio
ACCIAIO - Mass Density: 7850; Poisson Ratio: 0.3; Shear Modulus: 8000000000; Thermal Expansion Coefficient: 0.00001; Young Modulus: 20999999488

# Material: Acciaio
ACCIAIO - Mass Density: 7850; Poisson Ratio: 0.3; Shear Modulus: 8000000000; Thermal Expansion Coefficient: 0.00001; Young Modulus: 20999999488

# Material: Acciaio
ACCIAIO - Mass Density: 7850; Poisson Ratio: 0.3; Shear Modulus: 8000000000; Thermal Expansion Coefficient: 0.00001; Young Modulus: 20999999488

# Material: Acciaio
ACCIAIO - Mass Density: 7850; Poisson Ratio: 0.3; Shear Modulus: 8000000000; Thermal Expansion Coefficient: 0.00001; Young Modulus: 20999999488

# Material: Acciaio
ACCIAIO - Mass Density: 7850; Poisson Ratio: 0.3; Shear Modulus: 8000000000; Thermal Expansion Coefficient: 0.00001; Young Modulus: 20999999488

# Material: Acciaio
ACCIAIO - Mass Density: 7850; Poisson Ratio: 0.3; Shear Modulus: 8000000000; Thermal Expansion Coefficient: 0.00001; Young Modulus: 20999999488

# Material: Acciaio
ACCIAIO - Mass Density: 7850; Poisson Ratio: 0.3; Shear Modulus: 8000000000; Thermal Expansion Coefficient: 0.00001; Young Modulus: 20999999488

# Material: Acciaio
ACCIAIO - Mass Density: 7850; Poisson Ratio: 0.3; Shear Modulus: 8000000000; Thermal Expansion Coefficient: 0.00001; Young Modulus: 20999999488

# Material: Acciaio
ACCIAIO - Mass Density: 7850; Poisson Ratio: 0.3; Shear Modulus: 8000000000; Thermal Expansion Coefficient: 0.00001; Young Modulus: 20999999488

# Material: Acciaio
ACCIAIO - Mass Density: 7850; Poisson Ratio: 0.3; Shear Modulus: 8000000000; Thermal Expansion Coefficient: 0.00001; Young Modulus: 20999999488

# Material: Acciaio
ACCIAIO - Mass Density: 7850; Poisson Ratio: 0.3; Shear Modulus: 8000000000; Thermal Expansion Coefficient: 0.00001; Young Modulus: 20999999488

# Material: Acciaio
ACCIAIO - Mass Density: 7850; Poisson Ratio: 0.3; Shear Modulus: 8000000000; Thermal Expansion Coefficient: 0.00001; Young Modulus: 20999999488

# Material: Acciaio
ACCIAIO - Mass Density: 7850; Poisson Ratio: 0.3; Shear Modulus: 8000000000; Thermal Expansion Coefficient: 0.00001; Young Modulus: 20999999488

# Material: Acciaio
ACCIAIO - Mass Density: 7850; Poisson Ratio: 0.3; Shear Modulus: 8000000000; Thermal Expansion Coefficient: 0.00001; Young Modulus: 20999999488

# Material: Acciaio
ACCIAIO - Mass Density: 7850; Poisson Ratio: 0.3; Shear Modulus: 8000000000; Thermal Expansion Coefficient: 0.00001; Young Modulus: 20999999488

# Material: Acciaio
ACCIAIO - Mass Density: 7850; Poisson Ratio: 0.3; Shear Modulus: 8000000000; Thermal Expansion Coefficient: 0.00001; Young Modulus: 20999999488

# Material: Acciaio
ACCIAIO - Mass Density: 7850; Poisson Ratio: 0.3; Shear Modulus: 8000000000; Thermal Expansion Coefficient: 0.00001; Young Modulus: 20999999488

# Material: Acciaio
ACCIAIO - Mass Density: 7850; Poisson Ratio: 0.3; Shear Modulus: 8000000000; Thermal Expansion Coefficient: 0.00001; Young Modulus: 20999999488

# Material: Acciaio
ACCIAIO - Mass Density: 7850; Poisson Ratio: 0.3; Shear Modulus: 8000000000; Thermal Expansion Coefficient: 0.00001; Young Modulus: 20999999488

# Material: Acciaio
ACCIAIO - Mass Density: 7850; Poisson Ratio: 0.3; Shear Modulus: 8000000000; Thermal Expansion Coefficient: 0.00001; Young Modulus: 20999999488

# Material: Acciaio
ACCIAIO - Mass Density: 7850; Poisson Ratio: 0.3; Shear Modulus: 8000000000; Thermal Expansion Coefficient: 0.00001; Young Modulus: 20999999488

# Material: Acciaio
ACCIAIO - Mass Density: 7850; Poisson Ratio: 0.3; Shear Modulus: 8000000000; Thermal Expansion Coefficient: 0.00001; Young Modulus: 20999999488

# Material: Acciaio
ACCIAIO - Mass Density: 7850; Poisson Ratio: 0.3; Shear Modulus: 8000000000; Thermal Expansion Coefficient: 0.00001; Young Modulus: 20999999488

# Material: Acciaio
ACCIAIO - Mass Density: 7850; Poisson Ratio: 0.3; Shear Modulus: 8000000000; Thermal Expansion Coefficient: 0.00001; Young Modulus: 20999999488

# Material: Acciaio
ACCIAIO - Mass Density: 7850; Poisson Ratio: 0.3; Shear Modulus: 8000000000; Thermal Expansion Coefficient: 0.00001; Young Modulus: 20999999488

# Material: Acciaio
ACCIAIO - Mass Density: 7850; Poisson Ratio: 0.3; Shear Modulus: 8000000000; Thermal Expansion Coefficient: 0.00001; Young Modulus: 20999999488

# Material: Acciaio
ACCIAIO - Mass Density: 7850; Poisson Ratio: 0.3; Shear Modulus: 8000000000; Thermal Expansion Coefficient: 0.00001; Young Modulus: 20999999488

# Material: Acciaio
ACCIAIO - Mass Density: 7850; Poisson Ratio: 0.3; Shear Modulus: 8000000000; Thermal Expansion Coefficient: 0.00001; Young Modulus: 20999999488

# Material: Acciaio
ACCIAIO - Mass Density: 7850; Poisson Ratio: 0.3; Shear Modulus: 8000000000; Thermal Expansion Coefficient: 0.00001; Young Modulus: 20999999488

# Material: Acciaio
ACCIAIO - Mass Density: 7850; Poisson Ratio: 0.3; Shear Modulus: 8000000000; Thermal Expansion Coefficient: 0.00001; Young Modulus: 20999999488

# Material: Acciaio
ACCIAIO - Mass Density: 7850; Poisson Ratio: 0.3; Shear Modulus: 8000000000; Thermal Expansion Coefficient: 0.00001; Young Modulus: 20999999488

# Material: Acciaio
ACCIAIO - Mass Density: 7850; Poisson Ratio: 0.3; Shear Modulus: 8000000000; Thermal Expansion Coefficient: 0.00001; Young Modulus: 20999999488

# Material: Acciaio
ACCIAIO - Mass Density: 7850; Poisson Ratio: 0.3; Shear Modulus: 8000000000; Thermal Expansion Coefficient: 0.00001; Young Modulus: 20999999488

# Material: Acciaio
ACCIAIO - Mass Density: 7850; Poisson Ratio: 0.3; Shear Modulus: 8000000000; Thermal Expansion Coefficient: 0.00001; Young Modulus: 20999999488

# Material: Acciaio
ACCIAIO - Mass Density: 7850; Poisson Ratio: 0.3; Shear Modulus: 8000000000; Thermal Expansion Coefficient: 0.00001; Young Modulus: 20999999488

# Material: Acciaio
ACCIAIO - Mass Density: 7850; Poisson Ratio: 0.3; Shear Modulus: 8000000000; Thermal Expansion Coefficient: 0.00001; Young Modulus: 20999999488

# Material: Acciaio
ACCIAIO - Mass Density: 7850; Poisson Ratio: 0.3; Shear Modulus: 8000000000; Thermal Expansion Coefficient: 0.00001; Young Modulus: 20999999488

# Material: Acciaio
ACCIAIO - Mass Density: 7850; Poisson Ratio: 0.3; Shear Modulus: 8000000000; Thermal Expansion Coefficient: 0.00001; Young Modulus: 20999999488

# Material: Acciaio
ACCIAIO - Mass Density: 7850; Poisson Ratio: 0.3; Shear Modulus: 8000000000; Thermal Expansion Coefficient: 0.00001; Young Modulus: 20999999488

# Material: Acciaio
ACCIAIO - Mass Density: 7850; Poisson Ratio: 0.3; Shear Modulus: 8000000000; Thermal Expansion Coefficient: 0.00001; Young Modulus: 20999999488

# Material: Acciaio
ACCIAIO - Mass Density: 7850; Poisson Ratio: 0.3; Shear Modulus: 8000000000; Thermal Expansion Coefficient: 0.00001; Young Modulus: 20999999488

# Material: Acciaio
ACCIAIO - Mass Density: 7850; Poisson Ratio: 0.3; Shear Modulus: 8000000000; Thermal Expansion Coefficient: 0.00001; Young Modulus: 20999999488

# Material: Acciaio
ACCIAIO - Mass Density: 7850; Poisson Ratio: 0.3; Shear Modulus: 8000000000; Thermal Expansion Coefficient: 0.00001; Young Modulus: 20999999488

# Material: Acciaio
ACCIAIO - Mass Density: 7850; Poisson Ratio: 0.3; Shear Modulus: 8000000000; Thermal Expansion Coefficient: 0.00001; Young Modulus: 20999999488

# Material: Acciaio
ACCIAIO - Mass Density: 7850; Poisson Ratio: 0.3; Shear Modulus: 8000000000; Thermal Expansion Coefficient: 0.00001; Young Modulus: 20999999488

# Material: Acciaio
ACCIAIO - Mass Density: 7850; Poisson Ratio: 0.3; Shear Modulus: 8000000000; Thermal Expansion Coefficient: 0.00001; Young Modulus: 20999999488

# Material: Calcestruzzo classe C25/30
CEMENTO ARMATO - Mass Density: 2500; Poisson Ratio: 0.1; Shear Modulus: 1429420032; Thermal Expansion Coefficient: 0.00001; Young Modulus: 3144719872
